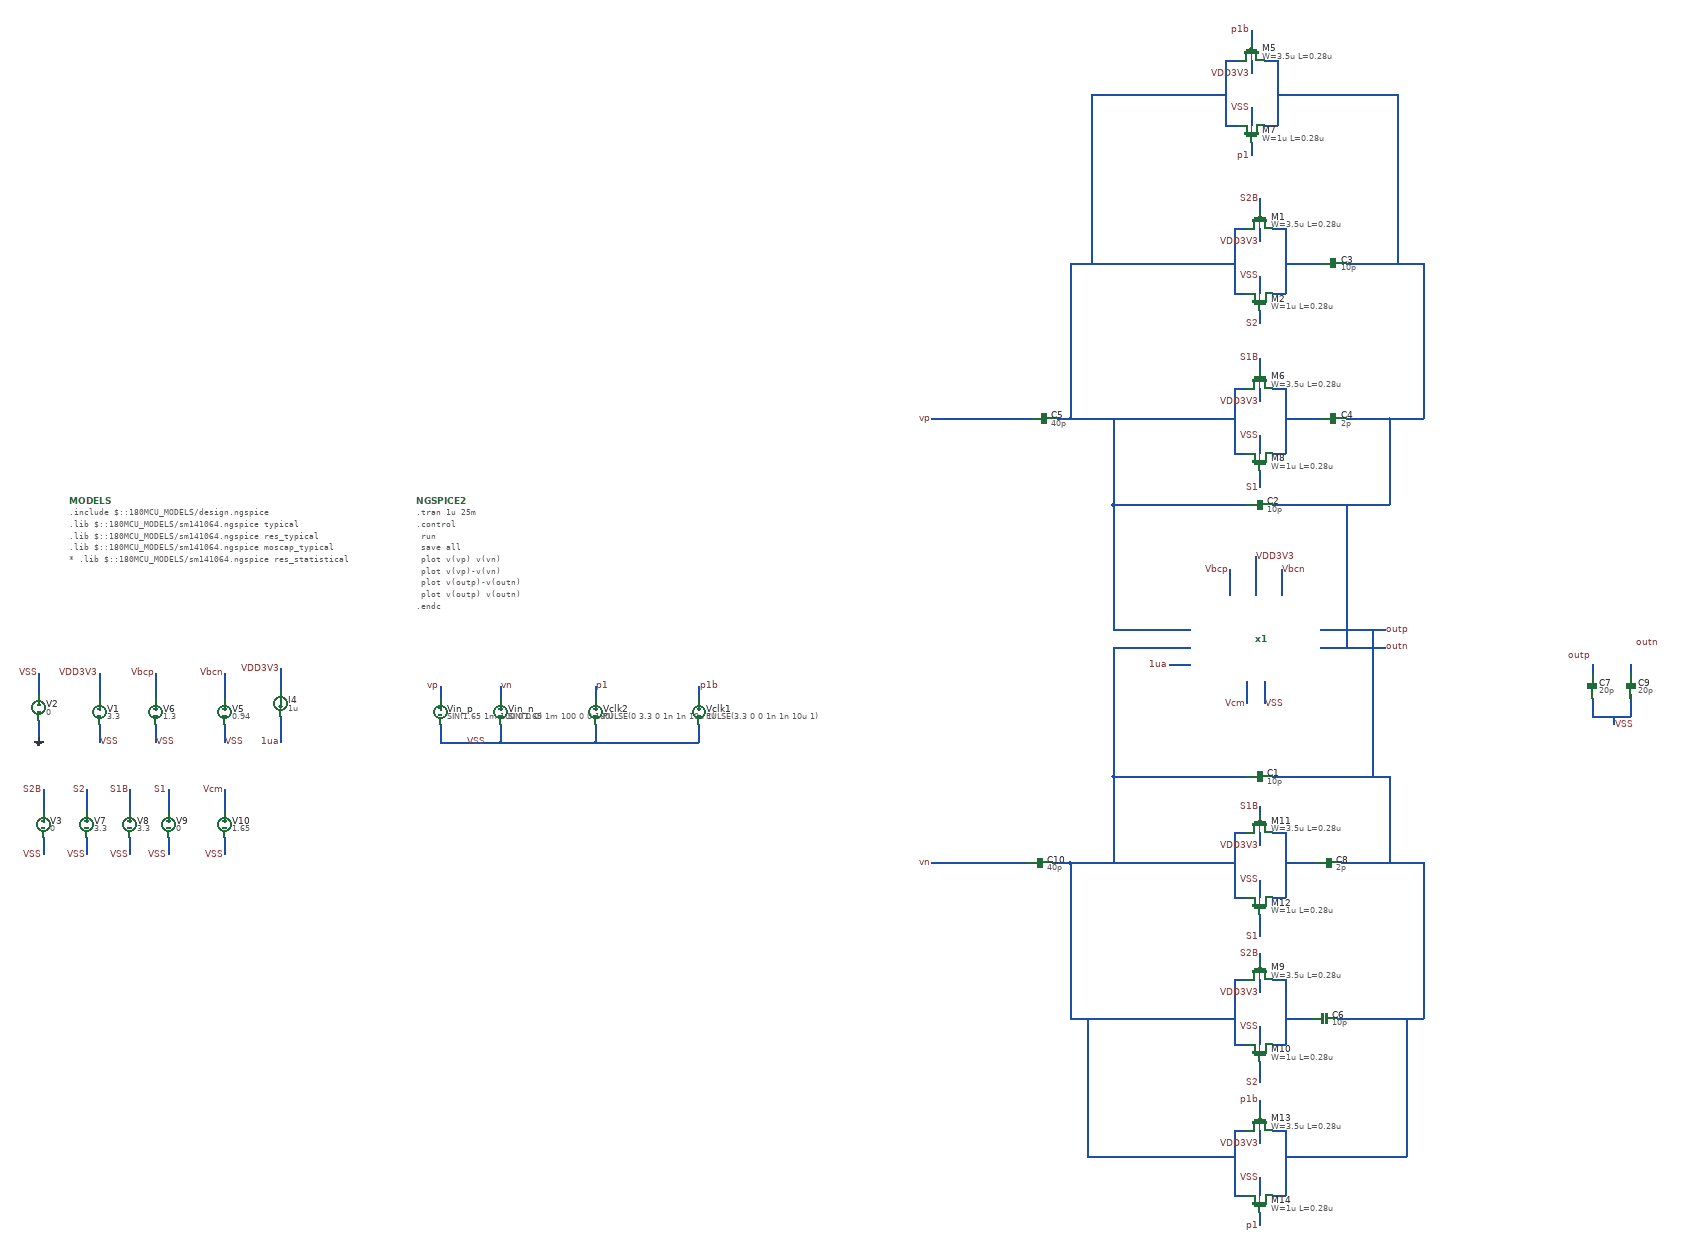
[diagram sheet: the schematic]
v {xschem version=3.4.8RC file_version=1.3}
G {}
K {}
V {}
S {}
F {}
E {}
P 4 1 3760 -2910 {}
N 1170 -1630 1170 -1580 {lab=VDD3V3}
N 1170 -1520 1170 -1460 {lab=1ua}
N 1040 -1500 1040 -1460 {lab=VSS}
N 1040 -1620 1040 -1560 {lab=Vbcn}
N 880 -1500 880 -1460 {lab=VSS}
N 880 -1620 880 -1560 {lab=Vbcp}
N 750 -1500 750 -1460 {lab=VSS}
N 750 -1620 750 -1560 {lab=VDD3V3}
N 610 -1510 610 -1480 {lab=0}
N 610 -1480 610 -1470 {lab=0}
N 610 -1620 610 -1570 {lab=VSS}
N 3450 -1600 3450 -1550 {lab=VSS}
N 3010 -2210 3140 -2210 {lab=#net1}
N 3200 -2210 3380 -2210 {lab=#net1}
N 3000 -2210 3010 -2210 {lab=#net1}
N 3100 -2010 3410 -2010 {lab=#net1}
N 3100 -2210 3100 -2010 {lab=#net1}
N 3470 -2010 3740 -2010 {lab=outn}
N 3740 -2210 3740 -2010 {lab=outn}
N 3010 -2570 3140 -2570 {lab=#net1}
N 3000 -2570 3010 -2570 {lab=#net1}
N 3000 -2570 3000 -2210 {lab=#net1}
N 3820 -2570 3820 -2210 {lab=outn}
N 3580 -1720 3730 -1720 {lab=outp}
N 3010 -1180 3140 -1180 {lab=#net2}
N 3200 -1180 3380 -1180 {lab=#net2}
N 3000 -1180 3010 -1180 {lab=#net2}
N 3100 -1380 3410 -1380 {lab=#net2}
N 3100 -1380 3100 -1180 {lab=#net2}
N 3470 -1380 3740 -1380 {lab=outp}
N 3740 -1380 3740 -1180 {lab=outp}
N 3010 -820 3140 -820 {lab=#net2}
N 3200 -820 3380 -820 {lab=#net2}
N 3000 -820 3010 -820 {lab=#net2}
N 3000 -1180 3000 -820 {lab=#net2}
N 3820 -1180 3820 -820 {lab=outp}
N 3580 -1680 3730 -1680 {lab=outn}
N 2680 -2210 2750 -2210 {lab=vp}
N 2680 -1180 2740 -1180 {lab=vn}
N 3100 -2010 3100 -1720 {lab=#net1}
N 3140 -2570 3380 -2570 {lab=#net1}
N 3500 -2570 3580 -2570 {lab=#net3}
N 3640 -2570 3820 -2570 {lab=outn}
N 3500 -2210 3580 -2210 {lab=#net4}
N 3640 -2210 3740 -2210 {lab=outn}
N 3740 -2210 3820 -2210 {lab=outn}
N 3140 -2210 3200 -2210 {lab=#net1}
N 3640 -2010 3640 -1680 {lab=outn}
N 3700 -1710 3700 -1380 {lab=outp}
N 2750 -2210 2870 -2210 {lab=vp}
N 2870 -2210 2910 -2210 {lab=vp}
N 2970 -2210 3000 -2210 {lab=#net1}
N 2960 -1180 3000 -1180 {lab=#net2}
N 2870 -1180 2900 -1180 {lab=vn}
N 2740 -1180 2870 -1180 {lab=vn}
N 3380 -2650 3410 -2650 {lab=#net1}
N 3380 -2650 3380 -2500 {lab=#net1}
N 3380 -2500 3410 -2500 {lab=#net1}
N 3470 -2650 3500 -2650 {lab=#net3}
N 3500 -2650 3500 -2500 {lab=#net3}
N 3470 -2500 3500 -2500 {lab=#net3}
N 3100 -1680 3100 -1380 {lab=#net2}
N 3700 -1720 3700 -1710 {lab=outp}
N 3140 -1180 3200 -1180 {lab=#net2}
N 3630 -1180 3820 -1180 {lab=outp}
N 3500 -1180 3570 -1180 {lab=#net5}
N 3620 -820 3810 -820 {lab=outp}
N 3810 -820 3820 -820 {lab=outp}
N 3140 -820 3200 -820 {lab=#net2}
N 3440 -2650 3440 -2620 {lab=VDD3V3}
N 3440 -2540 3440 -2500 {lab=VSS}
N 3380 -2280 3410 -2280 {lab=#net1}
N 3380 -2280 3380 -2130 {lab=#net1}
N 3380 -2130 3410 -2130 {lab=#net1}
N 3470 -2280 3500 -2280 {lab=#net4}
N 3500 -2280 3500 -2130 {lab=#net4}
N 3470 -2130 3500 -2130 {lab=#net4}
N 3440 -2280 3440 -2250 {lab=VDD3V3}
N 3440 -2170 3440 -2130 {lab=VSS}
N 3380 -910 3410 -910 {lab=#net2}
N 3380 -910 3380 -760 {lab=#net2}
N 3380 -760 3410 -760 {lab=#net2}
N 3470 -910 3500 -910 {lab=#net6}
N 3500 -910 3500 -760 {lab=#net6}
N 3470 -760 3500 -760 {lab=#net6}
N 3440 -910 3440 -880 {lab=VDD3V3}
N 3440 -800 3440 -760 {lab=VSS}
N 3380 -1250 3410 -1250 {lab=#net2}
N 3380 -1250 3380 -1100 {lab=#net2}
N 3380 -1100 3410 -1100 {lab=#net2}
N 3470 -1250 3500 -1250 {lab=#net5}
N 3500 -1250 3500 -1100 {lab=#net5}
N 3470 -1100 3500 -1100 {lab=#net5}
N 3440 -1250 3440 -1220 {lab=VDD3V3}
N 3440 -1140 3440 -1100 {lab=VSS}
N 1540 -1500 1540 -1460 {lab=VSS}
N 1680 -1500 1680 -1460 {lab=VSS}
N 1540 -1460 1680 -1460 {lab=VSS}
N 1540 -1590 1540 -1560 {lab=vp}
N 1680 -1590 1680 -1560 {lab=vn}
N 3440 -2720 3440 -2690 {lab=S2B}
N 3440 -2460 3440 -2430 {lab=S2}
N 3440 -2350 3440 -2320 {lab=S1B}
N 3440 -2090 3440 -2060 {lab=S1}
N 3440 -2060 3440 -2050 {lab=S1}
N 3440 -1310 3440 -1290 {lab=S1B}
N 3440 -1060 3440 -1010 {lab=S1}
N 3440 -970 3440 -950 {lab=S2B}
N 3440 -720 3440 -670 {lab=S2}
N 3500 -820 3560 -820 {lab=#net6}
N 620 -1240 620 -1210 {lab=VSS}
N 620 -1210 620 -1200 {lab=VSS}
N 620 -1350 620 -1300 {lab=S2B}
N 720 -1240 720 -1210 {lab=VSS}
N 720 -1210 720 -1200 {lab=VSS}
N 720 -1350 720 -1300 {lab=S2}
N 820 -1240 820 -1210 {lab=VSS}
N 820 -1210 820 -1200 {lab=VSS}
N 820 -1350 820 -1300 {lab=S1B}
N 910 -1240 910 -1210 {lab=VSS}
N 910 -1210 910 -1200 {lab=VSS}
N 910 -1350 910 -1300 {lab=S1}
N 3100 -1720 3280 -1720 {lab=#net1}
N 3100 -1680 3280 -1680 {lab=#net2}
N 3230 -1640 3280 -1640 {lab=1ua}
N 3430 -1890 3430 -1800 {lab=VDD3V3}
N 3490 -1860 3490 -1800 {lab=Vbcn}
N 3410 -1600 3410 -1550 {lab=Vcm}
N 1040 -1240 1040 -1210 {lab=VSS}
N 1040 -1210 1040 -1200 {lab=VSS}
N 1040 -1350 1040 -1300 {lab=Vcm}
N 4210 -1640 4210 -1620 {lab=#net7}
N 4300 -1640 4300 -1620 {lab=#net8}
N 4210 -1560 4210 -1520 {lab=VSS}
N 4210 -1520 4300 -1520 {lab=VSS}
N 4300 -1570 4300 -1520 {lab=VSS}
N 4260 -1520 4260 -1500 {lab=VSS}
N 3370 -1860 3370 -1800 {lab=Vbcp}
N 3760 -2910 3760 -2570 {lab=outn}
N 3050 -2910 3050 -2570 {lab=#net1}
N 3040 -500 3320 -500 {lab=#net2}
N 3040 -820 3040 -500 {lab=#net2}
N 3540 -500 3780 -500 {lab=outp}
N 3780 -820 3780 -500 {lab=outp}
N 3360 -3040 3390 -3040 {lab=#net1}
N 3360 -3040 3360 -2890 {lab=#net1}
N 3360 -2890 3390 -2890 {lab=#net1}
N 3450 -3040 3480 -3040 {lab=outn}
N 3480 -3040 3480 -2890 {lab=outn}
N 3450 -2890 3480 -2890 {lab=outn}
N 3420 -3040 3420 -3010 {lab=VDD3V3}
N 3420 -2930 3420 -2890 {lab=VSS}
N 3420 -3110 3420 -3080 {lab=p1b}
N 3420 -2850 3420 -2820 {lab=p1}
N 3480 -2960 3760 -2960 {lab=outn}
N 3760 -2960 3760 -2920 {lab=outn}
N 3760 -2920 3760 -2910 {lab=outn}
N 3050 -2960 3360 -2960 {lab=#net1}
N 3050 -2960 3050 -2910 {lab=#net1}
N 3380 -560 3410 -560 {lab=#net2}
N 3380 -560 3380 -410 {lab=#net2}
N 3380 -410 3410 -410 {lab=#net2}
N 3470 -560 3500 -560 {lab=outp}
N 3500 -560 3500 -410 {lab=outp}
N 3470 -410 3500 -410 {lab=outp}
N 3440 -560 3440 -530 {lab=VDD3V3}
N 3440 -450 3440 -410 {lab=VSS}
N 3440 -630 3440 -600 {lab=p1b}
N 3440 -370 3440 -340 {lab=p1}
N 3500 -500 3540 -500 {lab=outp}
N 3320 -500 3370 -500 {lab=#net2}
N 3370 -500 3380 -500 {lab=#net2}
N 1900 -1500 1900 -1460 {lab=VSS}
N 1900 -1590 1900 -1560 {lab=p1}
N 2140 -1500 2140 -1460 {lab=VSS}
N 2140 -1590 2140 -1560 {lab=p1b}
N 1900 -1460 2140 -1460 {lab=VSS}
N 1680 -1460 1900 -1460 {lab=VSS}
C {isource.sym} 1170 -1550 0 0 {name=I4 value=1u}
C {lab_pin.sym} 1170 -1460 0 0 {name=p61 sig_type=std_logic lab=1ua}
C {vsource.sym} 1040 -1530 0 0 {name=V5 value=0.94 savecurrent=false}
C {vsource.sym} 880 -1530 0 0 {name=V6 value=1.3 savecurrent=false}
C {lab_pin.sym} 880 -1620 0 0 {name=p24 sig_type=std_logic lab=Vbcp}
C {lab_pin.sym} 1040 -1620 0 0 {name=p12 sig_type=std_logic lab=Vbcn}
C {lab_wire.sym} 880 -1460 0 1 {name=p32 sig_type=std_logic lab=VSS}
C {lab_wire.sym} 1040 -1460 0 1 {name=p43 sig_type=std_logic lab=VSS}
C {vsource.sym} 750 -1530 0 0 {name=V1 value=3.3 savecurrent=false}
C {lab_pin.sym} 750 -1620 0 0 {name=p5 sig_type=std_logic lab=VDD3V3}
C {lab_wire.sym} 610 -1620 0 0 {name=p15 sig_type=std_logic lab=VSS}
C {vsource.sym} 610 -1540 0 0 {name=V2 value=0 savecurrent=false}
C {lab_wire.sym} 750 -1460 0 1 {name=p42 sig_type=std_logic lab=VSS}
C {gnd.sym} 610 -1470 0 0 {name=l1 lab=0}
C {lab_pin.sym} 1170 -1630 0 0 {name=p1 sig_type=std_logic lab=VDD3V3}
C {lab_pin.sym} 3230 -1640 0 0 {name=p2 sig_type=std_logic lab=1ua}
C {lab_wire.sym} 3450 -1550 0 1 {name=p3 sig_type=std_logic lab=VSS}
C {lab_pin.sym} 3430 -1890 0 1 {name=p4 sig_type=std_logic lab=VDD3V3}
C {capa.sym} 3610 -2570 3 1 {name=C3
m=1
value=10p
footprint=1206
device="ceramic capacitor"}
C {capa.sym} 2940 -2210 1 0 {name=C5
m=1
value=40p
footprint=1206
device="ceramic capacitor"}
C {capa.sym} 2930 -1180 1 1 {name=C10
m=1
value=40p
footprint=1206
device="ceramic capacitor"}
C {lab_pin.sym} 3730 -1720 0 1 {name=p11 sig_type=std_logic lab=outp}
C {lab_pin.sym} 3730 -1680 0 1 {name=p13 sig_type=std_logic lab=outn}
C {capa.sym} 3610 -2210 3 1 {name=C4
m=1
value=2p
footprint=1206
device="ceramic capacitor"}
C {lab_wire.sym} 2680 -2210 0 0 {name=p14 sig_type=std_logic lab=vp}
C {lab_wire.sym} 2680 -1180 0 0 {name=p16 sig_type=std_logic lab=vn}
C {symbols/pfet_03v3.sym} 3440 -2670 1 0 {name=M1
L=0.28u
W=3.5u
nf=1
m=1
ad="'int((nf+1)/2) * W/nf * 0.18u'"
pd="'2*int((nf+1)/2) * (W/nf + 0.18u)'"
as="'int((nf+2)/2) * W/nf * 0.18u'"
ps="'2*int((nf+2)/2) * (W/nf + 0.18u)'"
nrd="'0.18u / W'" nrs="'0.18u / W'"
sa=0 sb=0 sd=0
model=pfet_03v3
spiceprefix=X
}
C {symbols/nfet_03v3.sym} 3440 -2480 1 1 {name=M2
L=0.28u
W=1u
nf=1
m=1
ad="'int((nf+1)/2) * W/nf * 0.18u'"
pd="'2*int((nf+1)/2) * (W/nf + 0.18u)'"
as="'int((nf+2)/2) * W/nf * 0.18u'"
ps="'2*int((nf+2)/2) * (W/nf + 0.18u)'"
nrd="'0.18u / W'" nrs="'0.18u / W'"
sa=0 sb=0 sd=0
model=nfet_03v3
spiceprefix=X
}
C {capa.sym} 3440 -1380 3 1 {name=C1
m=1
value=10p
footprint=1206
device="ceramic capacitor"}
C {capa.sym} 3590 -820 3 1 {name=C6
m=1
value=10p
footprint=1206
device="ceramic capacitor"}
C {lab_pin.sym} 3440 -2620 0 0 {name=p17 sig_type=std_logic lab=VDD3V3}
C {lab_wire.sym} 3440 -2540 0 0 {name=p18 sig_type=std_logic lab=VSS}
C {symbols/pfet_03v3.sym} 3440 -2300 1 0 {name=M6
L=0.28u
W=3.5u
nf=1
m=1
ad="'int((nf+1)/2) * W/nf * 0.18u'"
pd="'2*int((nf+1)/2) * (W/nf + 0.18u)'"
as="'int((nf+2)/2) * W/nf * 0.18u'"
ps="'2*int((nf+2)/2) * (W/nf + 0.18u)'"
nrd="'0.18u / W'" nrs="'0.18u / W'"
sa=0 sb=0 sd=0
model=pfet_03v3
spiceprefix=X
}
C {symbols/nfet_03v3.sym} 3440 -2110 1 1 {name=M8
L=0.28u
W=1u
nf=1
m=1
ad="'int((nf+1)/2) * W/nf * 0.18u'"
pd="'2*int((nf+1)/2) * (W/nf + 0.18u)'"
as="'int((nf+2)/2) * W/nf * 0.18u'"
ps="'2*int((nf+2)/2) * (W/nf + 0.18u)'"
nrd="'0.18u / W'" nrs="'0.18u / W'"
sa=0 sb=0 sd=0
model=nfet_03v3
spiceprefix=X
}
C {lab_pin.sym} 3440 -2250 0 0 {name=p21 sig_type=std_logic lab=VDD3V3}
C {lab_wire.sym} 3440 -2170 0 0 {name=p22 sig_type=std_logic lab=VSS}
C {symbols/pfet_03v3.sym} 3440 -930 1 0 {name=M9
L=0.28u
W=3.5u
nf=1
m=1
ad="'int((nf+1)/2) * W/nf * 0.18u'"
pd="'2*int((nf+1)/2) * (W/nf + 0.18u)'"
as="'int((nf+2)/2) * W/nf * 0.18u'"
ps="'2*int((nf+2)/2) * (W/nf + 0.18u)'"
nrd="'0.18u / W'" nrs="'0.18u / W'"
sa=0 sb=0 sd=0
model=pfet_03v3
spiceprefix=X
}
C {symbols/nfet_03v3.sym} 3440 -740 1 1 {name=M10
L=0.28u
W=1u
nf=1
m=1
ad="'int((nf+1)/2) * W/nf * 0.18u'"
pd="'2*int((nf+1)/2) * (W/nf + 0.18u)'"
as="'int((nf+2)/2) * W/nf * 0.18u'"
ps="'2*int((nf+2)/2) * (W/nf + 0.18u)'"
nrd="'0.18u / W'" nrs="'0.18u / W'"
sa=0 sb=0 sd=0
model=nfet_03v3
spiceprefix=X
}
C {lab_pin.sym} 3440 -880 0 0 {name=p23 sig_type=std_logic lab=VDD3V3}
C {lab_wire.sym} 3440 -800 0 0 {name=p25 sig_type=std_logic lab=VSS}
C {symbols/pfet_03v3.sym} 3440 -1270 1 0 {name=M11
L=0.28u
W=3.5u
nf=1
m=1
ad="'int((nf+1)/2) * W/nf * 0.18u'"
pd="'2*int((nf+1)/2) * (W/nf + 0.18u)'"
as="'int((nf+2)/2) * W/nf * 0.18u'"
ps="'2*int((nf+2)/2) * (W/nf + 0.18u)'"
nrd="'0.18u / W'" nrs="'0.18u / W'"
sa=0 sb=0 sd=0
model=pfet_03v3
spiceprefix=X
}
C {symbols/nfet_03v3.sym} 3440 -1080 1 1 {name=M12
L=0.28u
W=1u
nf=1
m=1
ad="'int((nf+1)/2) * W/nf * 0.18u'"
pd="'2*int((nf+1)/2) * (W/nf + 0.18u)'"
as="'int((nf+2)/2) * W/nf * 0.18u'"
ps="'2*int((nf+2)/2) * (W/nf + 0.18u)'"
nrd="'0.18u / W'" nrs="'0.18u / W'"
sa=0 sb=0 sd=0
model=nfet_03v3
spiceprefix=X
}
C {lab_pin.sym} 3440 -1220 0 0 {name=p26 sig_type=std_logic lab=VDD3V3}
C {lab_wire.sym} 3440 -1140 0 0 {name=p27 sig_type=std_logic lab=VSS}
C {lab_pin.sym} 1540 -1590 0 0 {name=p71 sig_type=std_logic lab=vp}
C {lab_pin.sym} 1680 -1590 0 1 {name=p75 sig_type=std_logic lab=vn}
C {vsource.sym} 1540 -1530 0 1 {name=Vin_p value="SIN(1.65 1m 100 0 0 0)" savecurrent=false}
C {vsource.sym} 1680 -1530 0 0 {name=Vin_n value="SIN(1.65 1m 100 0 0 180)" savecurrent=false}
C {lab_wire.sym} 1600 -1460 0 1 {name=p80 sig_type=std_logic lab=VSS}
C {devices/code_shown.sym} 1485.119489031288 -2020 0 0 {name=NGSPICE2 only_toplevel=true
value="
.tran 1u 25m

.control
  run
  save all
  plot v(vp) v(vn)
  plot v(vp)-v(vn)
  plot v(outp)-v(outn)
  plot v(outp) v(outn)
.endc
"}
C {lab_wire.sym} 3440 -2430 0 0 {name=p39 sig_type=std_logic lab=S2}
C {lab_wire.sym} 3440 -2720 0 0 {name=p44 sig_type=std_logic lab=S2B}
C {lab_wire.sym} 3440 -2050 0 0 {name=p45 sig_type=std_logic lab=S1}
C {lab_wire.sym} 3440 -2350 0 0 {name=p46 sig_type=std_logic lab=S1B}
C {lab_wire.sym} 3440 -1010 0 0 {name=p47 sig_type=std_logic lab=S1}
C {lab_wire.sym} 3440 -1310 0 0 {name=p48 sig_type=std_logic lab=S1B}
C {lab_wire.sym} 3440 -670 0 0 {name=p49 sig_type=std_logic lab=S2}
C {lab_wire.sym} 3440 -970 0 0 {name=p50 sig_type=std_logic lab=S2B}
C {lab_wire.sym} 620 -1200 0 0 {name=p64 sig_type=std_logic lab=VSS}
C {lab_wire.sym} 620 -1350 0 0 {name=p65 sig_type=std_logic lab=S2B}
C {lab_wire.sym} 720 -1200 0 0 {name=p66 sig_type=std_logic lab=VSS}
C {vsource.sym} 720 -1270 0 0 {name=V7 value=3.3 savecurrent=false}
C {lab_wire.sym} 720 -1350 0 0 {name=p67 sig_type=std_logic lab=S2}
C {lab_wire.sym} 820 -1200 0 0 {name=p68 sig_type=std_logic lab=VSS}
C {vsource.sym} 820 -1270 0 0 {name=V8 value=3.3 savecurrent=false}
C {lab_wire.sym} 820 -1350 0 0 {name=p69 sig_type=std_logic lab=S1B}
C {lab_wire.sym} 910 -1200 0 0 {name=p70 sig_type=std_logic lab=VSS}
C {vsource.sym} 910 -1270 0 0 {name=V9 value=0 savecurrent=false}
C {lab_wire.sym} 910 -1350 0 0 {name=p72 sig_type=std_logic lab=S1}
C {/foss/designs/folded_cascode/folded_cascode_v2.sym} 3430 -1700 0 0 {name=x1}
C {lab_wire.sym} 3410 -1550 0 0 {name=p73 sig_type=std_logic lab=Vcm}
C {lab_wire.sym} 1040 -1350 0 0 {name=p74 sig_type=std_logic lab=Vcm}
C {lab_wire.sym} 1040 -1200 0 0 {name=p76 sig_type=std_logic lab=VSS}
C {vsource.sym} 1040 -1270 0 0 {name=V10 value=1.65 savecurrent=false}
C {lab_pin.sym} 3370 -1860 0 0 {name=p77 sig_type=std_logic lab=Vbcp}
C {lab_pin.sym} 3490 -1860 0 1 {name=p6 sig_type=std_logic lab=Vbcn}
C {devices/code_shown.sym} 680 -2020 0 0 {name=MODELS only_toplevel=true
format="tcleval( @value )"
value="
.include $::180MCU_MODELS/design.ngspice
.lib $::180MCU_MODELS/sm141064.ngspice typical
.lib $::180MCU_MODELS/sm141064.ngspice res_typical
.lib $::180MCU_MODELS/sm141064.ngspice moscap_typical
* .lib $::180MCU_MODELS/sm141064.ngspice res_statistical
"}
C {capa.sym} 4210 -1590 0 0 {name=C7
m=1
value=20p
footprint=1206
device="ceramic capacitor"}
C {lab_wire.sym} 4260 -1500 0 1 {name=p7 sig_type=std_logic lab=VSS}
C {capa.sym} 4300 -1590 0 0 {name=C9
m=1
value=20p
footprint=1206
device="ceramic capacitor"}
C {lab_pin.sym} 4210 -1660 0 0 {name=p78 sig_type=std_logic lab=outp}
C {lab_pin.sym} 4310 -1690 0 1 {name=p79 sig_type=std_logic lab=outn}
C {vsource.sym} 620 -1270 0 0 {name=V3 value=0 savecurrent=false}
C {capa.sym} 3600 -1180 3 1 {name=C8
m=1
value=2p
footprint=1206
device="ceramic capacitor"}
C {capa.sym} 3440 -2010 3 1 {name=C2
m=1
value=10p
footprint=1206
device="ceramic capacitor"}
C {symbols/pfet_03v3.sym} 3420 -3060 1 0 {name=M5
L=0.28u
W=3.5u
nf=1
m=1
ad="'int((nf+1)/2) * W/nf * 0.18u'"
pd="'2*int((nf+1)/2) * (W/nf + 0.18u)'"
as="'int((nf+2)/2) * W/nf * 0.18u'"
ps="'2*int((nf+2)/2) * (W/nf + 0.18u)'"
nrd="'0.18u / W'" nrs="'0.18u / W'"
sa=0 sb=0 sd=0
model=pfet_03v3
spiceprefix=X
}
C {symbols/nfet_03v3.sym} 3420 -2870 1 1 {name=M7
L=0.28u
W=1u
nf=1
m=1
ad="'int((nf+1)/2) * W/nf * 0.18u'"
pd="'2*int((nf+1)/2) * (W/nf + 0.18u)'"
as="'int((nf+2)/2) * W/nf * 0.18u'"
ps="'2*int((nf+2)/2) * (W/nf + 0.18u)'"
nrd="'0.18u / W'" nrs="'0.18u / W'"
sa=0 sb=0 sd=0
model=nfet_03v3
spiceprefix=X
}
C {lab_pin.sym} 3420 -3010 0 0 {name=p8 sig_type=std_logic lab=VDD3V3}
C {lab_wire.sym} 3420 -2930 0 0 {name=p9 sig_type=std_logic lab=VSS}
C {symbols/pfet_03v3.sym} 3440 -580 1 0 {name=M13
L=0.28u
W=3.5u
nf=1
m=1
ad="'int((nf+1)/2) * W/nf * 0.18u'"
pd="'2*int((nf+1)/2) * (W/nf + 0.18u)'"
as="'int((nf+2)/2) * W/nf * 0.18u'"
ps="'2*int((nf+2)/2) * (W/nf + 0.18u)'"
nrd="'0.18u / W'" nrs="'0.18u / W'"
sa=0 sb=0 sd=0
model=pfet_03v3
spiceprefix=X
}
C {symbols/nfet_03v3.sym} 3440 -390 1 1 {name=M14
L=0.28u
W=1u
nf=1
m=1
ad="'int((nf+1)/2) * W/nf * 0.18u'"
pd="'2*int((nf+1)/2) * (W/nf + 0.18u)'"
as="'int((nf+2)/2) * W/nf * 0.18u'"
ps="'2*int((nf+2)/2) * (W/nf + 0.18u)'"
nrd="'0.18u / W'" nrs="'0.18u / W'"
sa=0 sb=0 sd=0
model=nfet_03v3
spiceprefix=X
}
C {lab_pin.sym} 3440 -530 0 0 {name=p20 sig_type=std_logic lab=VDD3V3}
C {lab_wire.sym} 3440 -450 0 0 {name=p28 sig_type=std_logic lab=VSS}
C {lab_wire.sym} 3440 -340 0 0 {name=p29 sig_type=std_logic lab=p1}
C {lab_wire.sym} 3440 -630 0 0 {name=p30 sig_type=std_logic lab=p1b}
C {lab_wire.sym} 3420 -2820 0 0 {name=p31 sig_type=std_logic lab=p1}
C {lab_wire.sym} 3420 -3110 0 0 {name=p33 sig_type=std_logic lab=p1b}
C {lab_pin.sym} 1900 -1590 0 1 {name=p62 sig_type=std_logic lab=p1}
C {lab_pin.sym} 2140 -1590 0 1 {name=p63 sig_type=std_logic lab=p1b}
C {vsource.sym} 1900 -1530 0 0 {name=Vclk2 value="PULSE(0 3.3 0 1n 1n 10u 1)" savecurrent=false}
C {vsource.sym} 2140 -1530 0 0 {name=Vclk1 value="PULSE(3.3 0 0 1n 1n 10u 1)" savecurrent=false}
